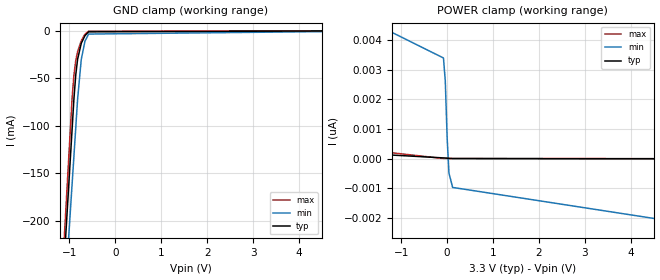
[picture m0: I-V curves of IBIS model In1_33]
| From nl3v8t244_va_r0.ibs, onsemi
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|//////////////////////////////////////////////////////////////////////////////
|//////////////////////////////////////////////////////////////////////////////
[Model]  In1_33
Model_type Input
Vinh = 2.00
Vinl = 0.80
|  variable   typ   min   max
C_comp   6.2pF   6.2pF   6.2pF
|//////////////////////////////////////////////////////////////////////////////
[Temperature Range]   25   125   -40
|//////////////////////////////////////////////////////////////////////////////
[Voltage Range]   3.30V   3.00V   3.60V
|//////////////////////////////////////////////////////////////////////////////
[POWER Clamp Reference] 3.30V   3.00V   3.60V
|//////////////////////////////////////////////////////////////////////////////
[GND Clamp Reference]   0V   0V   0V
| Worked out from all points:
|   GND clamp passes 1 mA (typ) near -0.56 V on its own axis
|//////////////////////////////////////////////////////////////////////////////
[GND Clamp]
|   Voltage   I(typ)   I(min)   I(max)
-3.3V     -2.005A    -1.921A    -2.113A
-1.18V    -297.1mA   -340.5mA   -277.8mA
-1.1V     -232.7mA   -280.8mA   -208.6mA
-1.04V    -184.3mA   -236.1mA   -156.7mA
-940mV    -103.8mA   -161.5mA   -71.06mA
-900mV    -71.57mA   -131.7mA   -46.56mA
-860mV    -46.57mA   -101.9mA   -31.39mA
-820mV    -30.09mA   -72.06mA   -22.12mA
-740mV    -13.38mA   -30.24mA   -10.68mA
-660mV    -5.326mA   -11.19mA   -3.739mA
-580mV    -1.331mA   -3.661mA   -656.1uA
6.6V      -4.579pA   6.697pA    2.174pA
|//////////////////////////////////////////////////////////////////////////////
[POWER Clamp]
|   Voltage   I(typ)   I(min)   I(max)
-3.3V     43.79nA    47.37nA    66.8nA
-2.6V     6.017nA    10.84nA    10.2nA
-2.4V     3.201nA    8.048nA    5.628nA
-2.2V     1.652nA    6.457nA    3.005nA
-2V       828.2pA    5.533nA    1.547nA
-1.5V     141.8pA    4.504nA    245.3pA
-80mV     20.18pA    3.407nA    -386.2fA
-40mV     16.17pA    2.629nA    -421.3fA
0V        11.07pA    715.9pA    -456.3fA
40mV      5.858pA    -496.3pA   -491.4fA
120mV     -1.423pA   -980.5pA   -561.5fA
6.6V      -14.66pA   -2.533nA   -6.243pA
